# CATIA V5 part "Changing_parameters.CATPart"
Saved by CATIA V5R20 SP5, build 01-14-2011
Part number: Changing parameters
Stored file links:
  C:\Users\lnj\Downloads\a1153_changing_parameters\Changing parameters.CATPart

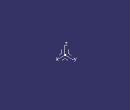
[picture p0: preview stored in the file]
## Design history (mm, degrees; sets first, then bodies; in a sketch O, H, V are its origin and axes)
Parameters
  Color = "Yellow"
  final_product = true
AxisSystem1: origin (0, 0, 0), X (1, 0, 0), Y (0, 1, 0), Z (0, 0, 1)
Body1 (main body)
  Body2
  Add1: tool Body2
  Body3
  Add2: tool Body3, deactivated
Relations
  Add1.Activity = final_product
  Add2.Activity = not(final_product )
